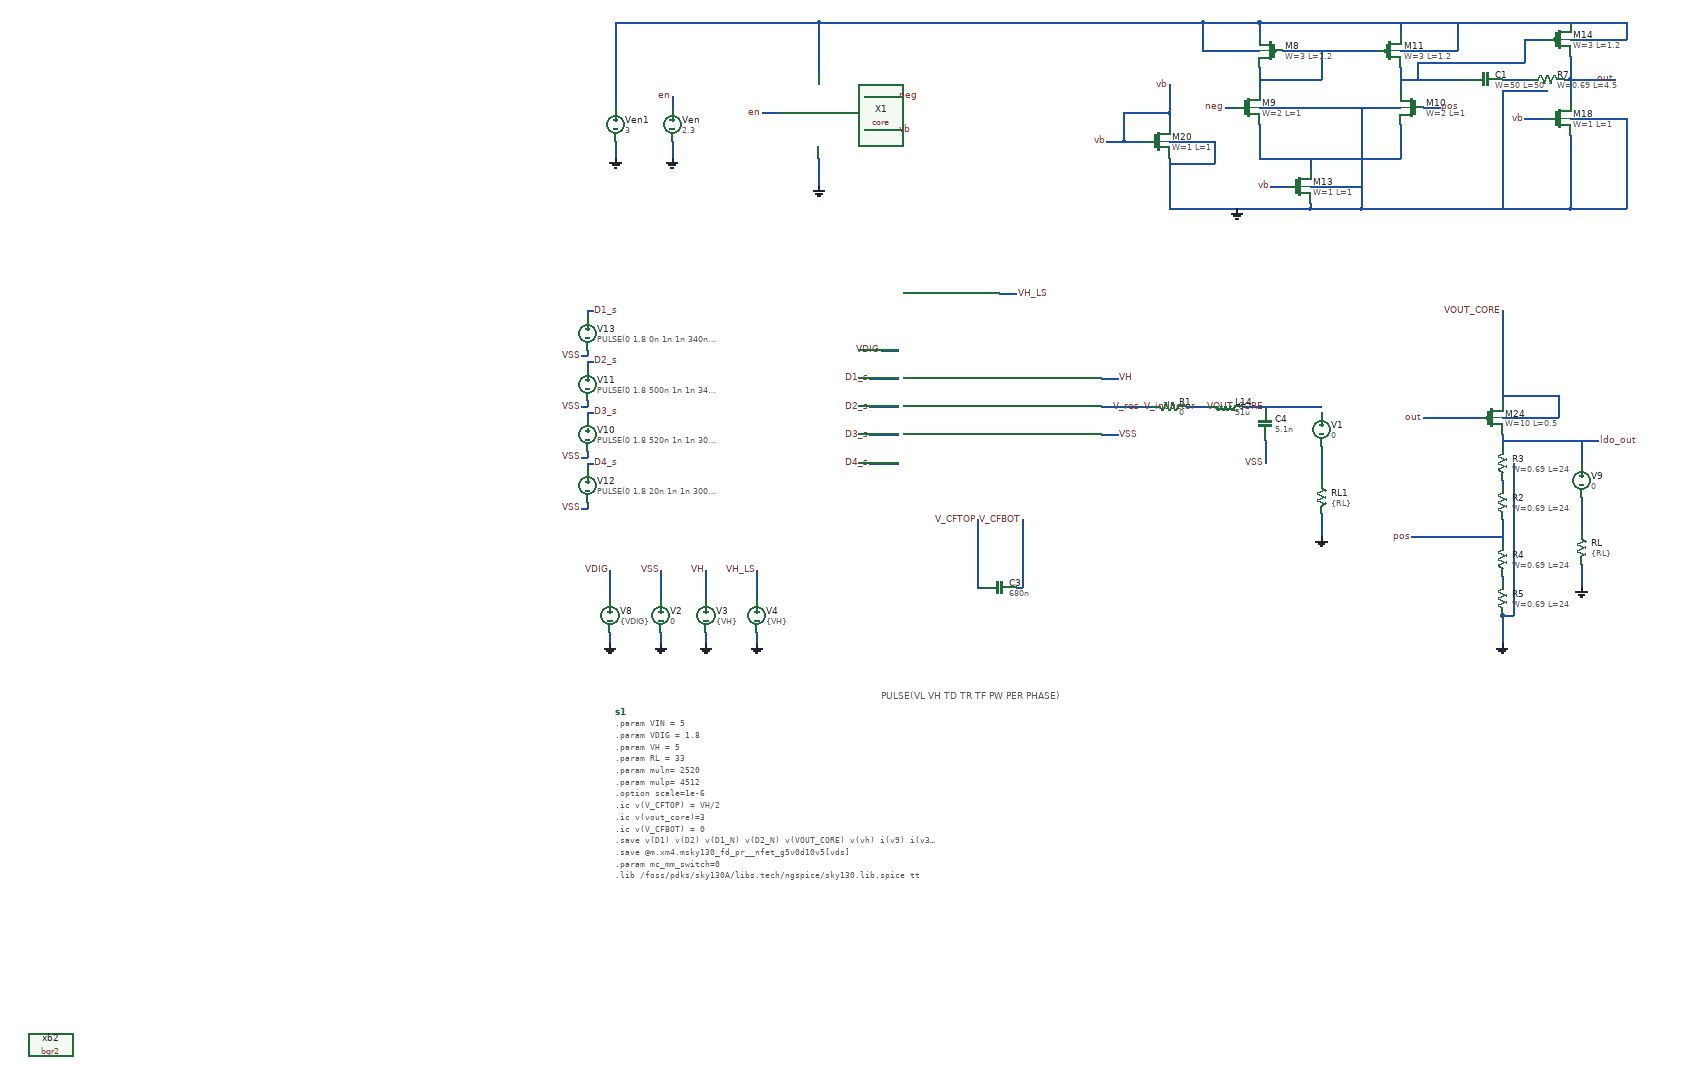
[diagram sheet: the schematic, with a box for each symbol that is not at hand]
v {xschem version=3.1.0 file_version=1.2
}
G {}
K {}
V {}
S {}
E {}
T {PULSE(VL VH TD TR TF PW PER PHASE) } -730 -100 0 0 0.4 0.4 {}
N -1120 -200 -1120 -180 { lab=GND}
N -1120 -310 -1120 -260 { lab=VSS}
N -1040 -200 -1040 -180 { lab=GND}
N -1040 -310 -1040 -260 { lab=VH}
N -750 -650 -700 -650 {
lab=D1_s}
N -750 -600 -700 -600 {
lab=D2_s}
N -750 -550 -700 -550 {
lab=D3_s}
N -750 -500 -700 -500 {
lab=D4_s}
N -340 -600 -270 -600 {
lab=V_res}
N -340 -650 -310 -650 {
lab=VH}
N -340 -550 -310 -550 {
lab=VSS}
N 510 -320 510 -280 {
lab=GND}
N -90 -600 -60 -600 {
lab=VOUT_CORE}
N -1210 -200 -1210 -180 { lab=GND}
N -1210 -310 -1210 -260 { lab=VDIG}
N -730 -700 -700 -700 {
lab=VDIG}
N -950 -200 -950 -180 { lab=GND}
N -950 -310 -950 -260 { lab=VH_LS}
N 510 -440 510 -380 {
lab=#net1}
N -50 -540 -50 -500 {
lab=VSS}
N -190 -600 -150 -600 {
lab=V_inductor}
N -270 -600 -250 -600 {
lab=V_res}
N -520 -800 -490 -800 {
lab=VH_LS}
N -560 -280 -550 -280 {
lab=V_CFTOP}
N -490 -280 -480 -280 {
lab=V_CFBOT}
N -560 -400 -560 -280 {
lab=V_CFTOP}
N -480 -400 -480 -280 {
lab=V_CFBOT}
N -940 -1120 -910 -1120 { lab=en}
N -1100 -1150 -1100 -1130 { lab=en}
N -840 -1040 -840 -990 { lab=GND}
N -1100 -1070 -1100 -1040 {
lab=GND}
N 370 -550 370 -530 { lab=ldo_out}
N 370 -380 370 -360 { lab=pos}
N 370 -690 370 -610 { lab=VOUT_CORE}
N 370 -580 470 -580 { lab=VOUT_CORE}
N 290 -370 370 -370 { lab=pos}
N 370 -770 370 -690 { lab=VOUT_CORE}
N 370 -470 370 -460 { lab=#net2}
N 370 -400 370 -390 { lab=pos}
N 390 -480 390 -430 { lab=GND}
N 390 -500 390 -480 { lab=GND}
N 370 -390 370 -380 { lab=pos}
N 370 -300 370 -290 { lab=#net3}
N 390 -330 390 -260 { lab=GND}
N 390 -260 390 -230 { lab=GND}
N 380 -230 390 -230 { lab=GND}
N 370 -230 380 -230 { lab=GND}
N 370 -230 370 -220 { lab=GND}
N 390 -420 390 -330 { lab=GND}
N 390 -430 390 -420 { lab=GND}
N 370 -230 370 -190 { lab=GND}
N 370 -190 370 -180 { lab=GND}
N 210 -370 290 -370 { lab=pos}
N 470 -620 470 -580 {
lab=VOUT_CORE}
N 370 -620 470 -620 {
lab=VOUT_CORE}
N -840 -1280 -840 -1190 {
lab=#net4}
N 230 -580 330 -580 {
lab=out}
N -60 -1280 -60 -1260 { lab=#net4}
N -60 -1280 190 -1280 { lab=#net4}
N 190 -1280 190 -1260 { lab=#net4}
N 190 -1200 190 -1160 { lab=#net5}
N -20 -1230 150 -1230 { lab=#net6}
N -60 -1200 -60 -1160 { lab=#net6}
N -60 -1100 -60 -1040 { lab=#net7}
N -60 -1040 190 -1040 { lab=#net7}
N 190 -1100 190 -1040 { lab=#net7}
N 30 -1040 30 -1020 { lab=#net7}
N -60 -1130 190 -1130 { lab=GND}
N 120 -1130 120 -950 { lab=GND}
N 30 -950 120 -950 { lab=GND}
N 190 -1230 290 -1230 { lab=#net4}
N 290 -1280 290 -1230 { lab=#net4}
N 180 -1280 290 -1280 { lab=#net4}
N -160 -1230 -60 -1230 { lab=#net4}
N -160 -1280 -160 -1230 { lab=#net4}
N -160 -1280 -60 -1280 { lab=#net4}
N 30 -990 120 -990 { lab=GND}
N 410 -1250 450 -1250 { lab=#net5}
N 280 -1280 410 -1280 { lab=#net4}
N 490 -1250 590 -1250 { lab=#net4}
N 490 -1280 590 -1280 { lab=#net4}
N 590 -1280 590 -1250 { lab=#net4}
N 490 -1220 490 -1180 { lab=out}
N 120 -950 410 -950 { lab=GND}
N 490 -950 580 -950 { lab=GND}
N 410 -1110 450 -1110 { lab=vb}
N -40 -990 -10 -990 { lab=vb}
N 50 -1230 50 -1180 { lab=#net6}
N -60 -1180 50 -1180 { lab=#net6}
N 410 -1180 420 -1180 { lab=#net8}
N 480 -1180 490 -1180 { lab=out}
N 490 -1180 490 -1140 { lab=out}
N 490 -1110 590 -1110 { lab=GND}
N 590 -1110 590 -950 { lab=GND}
N 580 -950 590 -950 { lab=GND}
N 490 -1080 490 -950 { lab=GND}
N -120 -1130 -100 -1130 { lab=neg}
N 230 -1130 260 -1130 { lab=pos}
N 410 -1250 410 -1210 { lab=#net5}
N 190 -1180 250 -1180 { lab=#net5}
N 220 -1210 330 -1210 { lab=#net5}
N 220 -1210 220 -1180 { lab=#net5}
N 490 -1180 550 -1180 { lab=out}
N 550 -1180 560 -1180 { lab=out}
N 560 -1180 570 -1180 { lab=out}
N 430 -1160 450 -1160 { lab=GND}
N 370 -1160 370 -950 { lab=GND}
N -300 -1070 -260 -1070 { lab=vb}
N -300 -1120 -300 -1070 { lab=vb}
N -300 -1120 -220 -1120 { lab=vb}
N -220 -1040 -220 -1020 { lab=GND}
N -220 -1070 -140 -1070 { lab=GND}
N -140 -1070 -140 -1030 { lab=GND}
N -220 -1030 -140 -1030 { lab=GND}
N -330 -1070 -300 -1070 { lab=vb}
N -220 -1120 -220 -1100 { lab=vb}
N -220 -1170 -220 -1120 { lab=vb}
N 30 -960 30 -950 { lab=GND}
N -220 -1020 -220 -950 { lab=GND}
N 330 -1210 410 -1210 { lab=#net5}
N 410 -1280 490 -1280 { lab=#net4}
N 410 -950 430 -950 { lab=GND}
N 430 -950 490 -950 { lab=GND}
N 370 -1160 430 -1160 { lab=GND}
N 250 -1180 310 -1180 { lab=#net5}
N 370 -1180 410 -1180 { lab=#net8}
N -1250 -770 -1250 -760 {
lab=D1_s}
N -1250 -770 -1240 -770 {
lab=D1_s}
N -1250 -700 -1250 -690 {
lab=VSS}
N -1260 -690 -1250 -690 {
lab=VSS}
N -1250 -680 -1250 -670 {
lab=D2_s}
N -1250 -680 -1240 -680 {
lab=D2_s}
N -1250 -610 -1250 -600 {
lab=VSS}
N -1260 -600 -1250 -600 {
lab=VSS}
N -1250 -590 -1250 -580 {
lab=D3_s}
N -1250 -590 -1240 -590 {
lab=D3_s}
N -1250 -520 -1250 -510 {
lab=VSS}
N -1260 -510 -1250 -510 {
lab=VSS}
N -1250 -500 -1250 -490 {
lab=D4_s}
N -1250 -500 -1240 -500 {
lab=D4_s}
N -1250 -430 -1250 -420 {
lab=VSS}
N -1260 -420 -1250 -420 {
lab=VSS}
N -60 -600 -50 -600 {
lab=VOUT_CORE}
N 370 -540 540 -540 {
lab=ldo_out}
N 510 -540 510 -500 {
lab=ldo_out}
N -1200 -1150 -1200 -1130 { lab=#net4}
N -1200 -1070 -1200 -1040 {
lab=GND}
N -1200 -1280 -1200 -1150 {
lab=#net4}
N -840 -1280 -260 -1280 {
lab=#net4}
N -260 -1280 -160 -1280 {
lab=#net4}
N -220 -950 30 -950 {
lab=GND}
N -760 -1150 -700 -1150 {
lab=neg}
N -760 -1090 -700 -1090 {
lab=vb}
N 50 -410 50 -370 {
lab=GND}
N 50 -530 50 -470 {
lab=#net9}
N -50 -600 50 -600 {
lab=VOUT_CORE}
N -1200 -1280 -840 -1280 {
lab=#net4}
C {devices/vsource.sym} -1120 -230 0 0 {name=V2 value=0}
C {devices/gnd.sym} -1120 -180 0 0 {name=l9 lab=GND}
C {devices/code_shown.sym} -1200 -60 0 0 {name=s1 only_toplevel=false value="
.param VIN = 5
.param VDIG = 1.8
.param VH = 5
.param RL = 33
.param muln= 2520
.param mulp= 4512
.option scale=1e-6
.ic v(V_CFTOP) = VH/2
.ic v(vout_core)=3
.ic v(V_CFBOT) = 0
.save v(D1) v(D2) v(D1_N) v(D2_N) v(VOUT_CORE) v(vh) i(v9) i(v3) i(v4) v(v_cftop,v_cfbot) v(D1,v_cftop) v(D2,vout_core) v(D2_N,v_cfbot) v(D1_Nv,VSS) v(v_out_ls1) v(v_out_ls2) v(d2_n,v_cfbot) v(D1_s) v(D2_s)	v(D3_s) v(D4_s)
.save @m.xm4.msky130_fd_pr__nfet_g5v0d10v5[vds]
.param mc_mm_switch=0

.lib /foss/pdks/sky130A/libs.tech/ngspice/sky130.lib.spice tt


.options savecurrents


.control
save all

save v(v_cftop,v_cfbot) v(D1) v(D2) v(D1_N) v(D2_N) v(VOUT_CORE) v(vh) i(v9) i(v3) i(v4) v(v_cftop,v_cfbot) v(D1,v_cftop) v(D2,vout_core) v(D2_N,v_cfbot) v(D1_Nv,VSS) v(v_out_ls1) v(v_out_ls2) v(d2_n,v_cfbot) v(D1_s) v(D2_s)	v(D3_s) v(D4_s)
tran 1n 50u 20u
write signals.raw v(D1) v(D2) v(D1_N) v(D2_N) v(VOUT_CORE) v(vh) i(v9) i(v3) i(v4) v(v_cftop,v_cfbot) v(D1,v_cftop) v(D2,vout_core) v(D2_N,v_cfbot) v(D1_Nv,VSS) v(v_out_ls1) v(v_out_ls2) v(d2_n,v_cfbot) v(D1_s) v(D2_s)	v(D3_s) v(D4_s)
wrdata /foss/designs/IPD413/Simulaciones/core_wfilter.txt v(vout_core) i(v3) i(v4) i(v9) v(v_cftop,v_cfbot)
plot v(VOUT_CORE) v(ldo_out)
plot v(out)

.endc
"}
C {devices/vsource.sym} -1040 -230 0 0 {name=V3 value=\{VH\}}
C {devices/gnd.sym} -1040 -180 0 0 {name=l23 lab=GND}
C {devices/lab_wire.sym} -1040 -310 0 0 {name=l24 sig_type=std_logic lab=VH}
C {devices/lab_wire.sym} -750 -650 0 0 {name=l18 sig_type=std_logic lab=D1_s}
C {devices/lab_wire.sym} -750 -600 0 0 {name=l20 sig_type=std_logic lab=D2_s}
C {devices/lab_wire.sym} -750 -550 0 0 {name=l25 sig_type=std_logic lab=D3_s}
C {devices/lab_wire.sym} -750 -500 0 0 {name=l26 sig_type=std_logic lab=D4_s}
C {devices/lab_wire.sym} -560 -400 0 0 {name=l27 sig_type=std_logic lab=V_CFTOP}
C {devices/lab_wire.sym} -480 -400 0 0 {name=l28 sig_type=std_logic lab=V_CFBOT}
C {devices/lab_wire.sym} -50 -600 3 1 {name=l29 sig_type=std_logic lab=VOUT_CORE}
C {devices/lab_wire.sym} -310 -650 2 0 {name=l32 sig_type=std_logic lab=VH}
C {devices/lab_wire.sym} -310 -550 2 0 {name=l33 sig_type=std_logic lab=VSS}
C {devices/res.sym} 510 -350 0 0 {name=RL
value=\{RL\}
footprint=1206
device=resistor
m=1}
C {devices/vsource.sym} -1210 -230 0 0 {name=V8 value=\{VDIG\}}
C {devices/gnd.sym} -1210 -180 0 0 {name=l2 lab=GND}
C {devices/lab_wire.sym} -1210 -310 0 0 {name=l3 sig_type=std_logic lab=VDIG}
C {devices/lab_wire.sym} -730 -700 0 0 {name=l4 sig_type=std_logic lab=VDIG}
C {devices/lab_wire.sym} -1120 -310 0 0 {name=l15 sig_type=std_logic lab=VSS}
C {devices/vsource.sym} -950 -230 0 0 {name=V4 value=\{VH\}}
C {devices/gnd.sym} -950 -180 0 0 {name=l12 lab=GND}
C {devices/lab_wire.sym} -950 -310 0 0 {name=l13 sig_type=std_logic lab=VH_LS}
C {devices/vsource.sym} 510 -470 0 0 {name=V9 value=0}
C {devices/capa.sym} -50 -570 0 0 {name=C4
m=1
value=5.1n
footprint=1206
device="ceramic capacitor"}
C {devices/lab_wire.sym} -50 -500 0 0 {name=l19 sig_type=std_logic lab=VSS}
C {devices/ind.sym} -120 -600 1 0 {name=L14
m=1
value=51u
footprint=1206
device=inductor}
C {devices/lab_wire.sym} -170 -600 1 1 {name=l21 sig_type=std_logic lab=V_inductor}
C {devices/res.sym} -220 -600 1 0 {name=R1
value=0
footprint=1206
device=resistor
m=1}
C {devices/lab_wire.sym} -270 -600 1 1 {name=l22 sig_type=std_logic lab=V_res}
C {devices/lab_wire.sym} -490 -800 2 0 {name=l16 sig_type=std_logic lab=VH_LS}
C {devices/capa.sym} -520 -280 3 0 {name=C3
m=1
value=680n
footprint=1206
device="ceramic capacitor"}
C {PMIC_lab-on-chip_power-management/DCDC_LDO_sim/core.sym} -760 -500 0 0 {name=X1}
C {PMIC_lab-on-chip_power-management/DCDC_LDO_sim/bgr2.sym} -2200 530 0 0 {name=xb2}
C {devices/vsource.sym} -1100 -1100 0 0 {name=Ven value=2.3}
C {devices/lab_pin.sym} -1100 -1150 0 0 {name=l46 sig_type=std_logic lab=en}
C {devices/lab_pin.sym} -940 -1120 0 0 {name=l51 sig_type=std_logic lab=en}
C {devices/gnd.sym} -1100 -1040 0 0 {name=l48 lab=GND}
C {sky130_fd_pr/pfet_g5v0d10v5.sym} 350 -580 0 0 {name=M24
L=0.5
W=10
nf=1
mult=800
ad="'int((nf+1)/2) * W/nf * 0.29'" 
pd="'2*int((nf+1)/2) * (W/nf + 0.29)'"
as="'int((nf+2)/2) * W/nf * 0.29'" 
ps="'2*int((nf+2)/2) * (W/nf + 0.29)'"
nrd="'0.29 / W'" nrs="'0.29 / W'"
sa=0 sb=0 sd=0
model=pfet_g5v0d10v5
spiceprefix=X
}
C {sky130_fd_pr/res_xhigh_po_0p69.sym} 370 -430 0 1 {name=R2
W=0.69
L=24
model=res_xhigh_po_0p69
spiceprefix=X
mult=3}
C {sky130_fd_pr/res_xhigh_po_0p69.sym} 370 -500 0 1 {name=R3
W=0.69
L=24
model=res_xhigh_po_0p69
spiceprefix=X
mult=8}
C {sky130_fd_pr/res_xhigh_po_0p69.sym} 370 -330 0 1 {name=R4
W=0.69
L=24
model=res_xhigh_po_0p69
spiceprefix=X
mult=2}
C {sky130_fd_pr/res_xhigh_po_0p69.sym} 370 -260 0 1 {name=R5
W=0.69
L=24
model=res_xhigh_po_0p69
spiceprefix=X
mult=4}
C {devices/gnd.sym} 510 -280 0 0 {name=l31 lab=GND}
C {devices/gnd.sym} -100 -950 0 0 {name=l34 lab=GND}
C {sky130_fd_pr/pfet_g5v0d10v5.sym} -40 -1230 0 1 {name=M8
L=1.2
W=3
nf=1
mult=4
ad="'int((nf+1)/2) * W/nf * 0.29'" 
pd="'2*int((nf+1)/2) * (W/nf + 0.29)'"
as="'int((nf+2)/2) * W/nf * 0.29'" 
ps="'2*int((nf+2)/2) * (W/nf + 0.29)'"
nrd="'0.29 / W'" nrs="'0.29 / W'"
sa=0 sb=0 sd=0
model=pfet_g5v0d10v5
spiceprefix=X
}
C {sky130_fd_pr/nfet_g5v0d10v5.sym} -80 -1130 0 0 {name=M9
L=1
W=2
nf=1
mult=8
ad="'int((nf+1)/2) * W/nf * 0.29'" 
pd="'2*int((nf+1)/2) * (W/nf + 0.29)'"
as="'int((nf+2)/2) * W/nf * 0.29'" 
ps="'2*int((nf+2)/2) * (W/nf + 0.29)'"
nrd="'0.29 / W'" nrs="'0.29 / W'"
sa=0 sb=0 sd=0
model=nfet_g5v0d10v5
spiceprefix=X
}
C {sky130_fd_pr/nfet_g5v0d10v5.sym} 210 -1130 0 1 {name=M10
L=1
W=2
nf=1
mult=8
ad="'int((nf+1)/2) * W/nf * 0.29'" 
pd="'2*int((nf+1)/2) * (W/nf + 0.29)'"
as="'int((nf+2)/2) * W/nf * 0.29'" 
ps="'2*int((nf+2)/2) * (W/nf + 0.29)'"
nrd="'0.29 / W'" nrs="'0.29 / W'"
sa=0 sb=0 sd=0
model=nfet_g5v0d10v5
spiceprefix=X
}
C {sky130_fd_pr/pfet_g5v0d10v5.sym} 170 -1230 0 0 {name=M11
L=1.2
W=3
nf=1
mult=4
ad="'int((nf+1)/2) * W/nf * 0.29'" 
pd="'2*int((nf+1)/2) * (W/nf + 0.29)'"
as="'int((nf+2)/2) * W/nf * 0.29'" 
ps="'2*int((nf+2)/2) * (W/nf + 0.29)'"
nrd="'0.29 / W'" nrs="'0.29 / W'"
sa=0 sb=0 sd=0
model=pfet_g5v0d10v5
spiceprefix=X
}
C {sky130_fd_pr/nfet_g5v0d10v5.sym} 10 -990 0 0 {name=M13
L=1
W=1
nf=1
mult=8
ad="'int((nf+1)/2) * W/nf * 0.29'" 
pd="'2*int((nf+1)/2) * (W/nf + 0.29)'"
as="'int((nf+2)/2) * W/nf * 0.29'" 
ps="'2*int((nf+2)/2) * (W/nf + 0.29)'"
nrd="'0.29 / W'" nrs="'0.29 / W'"
sa=0 sb=0 sd=0
model=nfet_g5v0d10v5
spiceprefix=X
}
C {sky130_fd_pr/pfet_g5v0d10v5.sym} 470 -1250 0 0 {name=M14
L=1.2
W=3
nf=1
mult=12
ad="'int((nf+1)/2) * W/nf * 0.29'" 
pd="'2*int((nf+1)/2) * (W/nf + 0.29)'"
as="'int((nf+2)/2) * W/nf * 0.29'" 
ps="'2*int((nf+2)/2) * (W/nf + 0.29)'"
nrd="'0.29 / W'" nrs="'0.29 / W'"
sa=0 sb=0 sd=0
model=pfet_g5v0d10v5
spiceprefix=X
}
C {sky130_fd_pr/nfet_g5v0d10v5.sym} 470 -1110 0 0 {name=M18
L=1
W=1
nf=1
mult=12
ad="'int((nf+1)/2) * W/nf * 0.29'" 
pd="'2*int((nf+1)/2) * (W/nf + 0.29)'"
as="'int((nf+2)/2) * W/nf * 0.29'" 
ps="'2*int((nf+2)/2) * (W/nf + 0.29)'"
nrd="'0.29 / W'" nrs="'0.29 / W'"
sa=0 sb=0 sd=0
model=nfet_g5v0d10v5
spiceprefix=X
}
C {devices/lab_pin.sym} -40 -990 0 0 {name=l36 sig_type=std_logic lab=vb}
C {devices/lab_pin.sym} 410 -1110 0 0 {name=l37 sig_type=std_logic lab=vb}
C {sky130_fd_pr/cap_mim_m3_1.sym} 340 -1180 3 1 {name=C1 model=cap_mim_m3_1 W=50 L=50 MF=1 spiceprefix=X}
C {sky130_fd_pr/res_xhigh_po_0p69.sym} 450 -1180 3 0 {name=R7
W=0.69
L=4.5
model=res_xhigh_po_0p69
spiceprefix=X
mult=1}
C {sky130_fd_pr/nfet_g5v0d10v5.sym} -240 -1070 0 0 {name=M20
L=1
W=1
nf=1
mult=4
ad="'int((nf+1)/2) * W/nf * 0.29'" 
pd="'2*int((nf+1)/2) * (W/nf + 0.29)'"
as="'int((nf+2)/2) * W/nf * 0.29'" 
ps="'2*int((nf+2)/2) * (W/nf + 0.29)'"
nrd="'0.29 / W'" nrs="'0.29 / W'"
sa=0 sb=0 sd=0
model=nfet_g5v0d10v5
spiceprefix=X
}
C {devices/lab_pin.sym} -330 -1070 0 0 {name=l38 sig_type=std_logic lab=vb}
C {devices/lab_pin.sym} -220 -1170 0 0 {name=l39 sig_type=std_logic lab=vb}
C {devices/lab_pin.sym} -700 -1090 2 0 {name=l40 sig_type=std_logic lab=vb}
C {devices/lab_pin.sym} -120 -1130 0 0 {name=p5 sig_type=std_logic lab=neg
}
C {devices/lab_pin.sym} -700 -1150 2 0 {name=p6 sig_type=std_logic lab=neg
}
C {devices/lab_pin.sym} 570 -1180 0 0 {name=l49 sig_type=std_logic lab=out}
C {devices/lab_pin.sym} 230 -580 0 0 {name=l50 sig_type=std_logic lab=out}
C {devices/lab_pin.sym} 260 -1130 2 0 {name=p2 sig_type=std_logic lab=pos

}
C {devices/lab_pin.sym} 210 -370 0 0 {name=p3 sig_type=std_logic lab=pos

}
C {devices/lab_wire.sym} -1240 -770 0 1 {name=l52 sig_type=std_logic lab=D1_s}
C {devices/vsource.sym} -1250 -550 0 0 {name=V10 value="PULSE(0 1.8 520n 1n 1n 300n 1000n)"}
C {devices/vsource.sym} -1250 -640 0 0 {name=V11 value="PULSE(0 1.8 500n 1n 1n 340n 1000n)"}
C {devices/lab_wire.sym} -1240 -680 0 1 {name=l53 sig_type=std_logic lab=D2_s}
C {devices/lab_pin.sym} -1240 -590 0 1 {name=l54 sig_type=std_logic lab=D3_s
}
C {devices/vsource.sym} -1250 -460 0 0 {name=V12 value="PULSE(0 1.8 20n 1n 1n 300n 1000n)"}
C {devices/lab_pin.sym} -1240 -500 0 1 {name=l55 sig_type=std_logic lab=D4_s
}
C {devices/lab_wire.sym} -1260 -420 0 0 {name=l56 sig_type=std_logic lab=VSS}
C {devices/lab_wire.sym} -1260 -690 0 0 {name=l57 sig_type=std_logic lab=VSS}
C {devices/lab_wire.sym} -1260 -600 0 0 {name=l58 sig_type=std_logic lab=VSS}
C {devices/lab_wire.sym} -1260 -510 0 0 {name=l59 sig_type=std_logic lab=VSS}
C {devices/vsource.sym} -1250 -730 0 0 {name=V13 value="PULSE(0 1.8 0n 1n 1n 340n 1000n)"}
C {devices/lab_pin.sym} 540 -540 2 0 {name=p1 sig_type=std_logic lab=ldo_out

}
C {devices/vsource.sym} -1200 -1100 0 0 {name=Ven1 value=3}
C {devices/gnd.sym} -1200 -1040 0 0 {name=l6 lab=GND}
C {devices/lab_wire.sym} 370 -770 3 1 {name=l7 sig_type=std_logic lab=VOUT_CORE}
C {devices/gnd.sym} 370 -180 0 0 {name=l1 lab=GND}
C {devices/gnd.sym} -840 -990 0 0 {name=l5 lab=GND}
C {devices/res.sym} 50 -440 0 0 {name=RL1
value=\{RL\}
footprint=1206
device=resistor
m=1}
C {devices/vsource.sym} 50 -560 0 0 {name=V1 value=0}
C {devices/gnd.sym} 50 -370 0 0 {name=l8 lab=GND}
